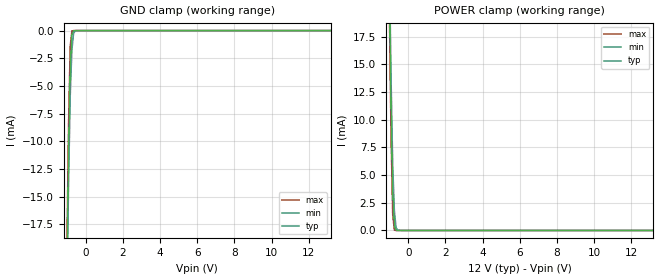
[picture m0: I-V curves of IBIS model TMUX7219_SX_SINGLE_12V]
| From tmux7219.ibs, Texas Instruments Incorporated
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[Model]   TMUX7219_SX_SINGLE_12V
Model_type   Terminator
|   typ   min   max
C_comp   44pF   44pF   44pF
[Voltage Range]   12   10.8   13.2
[Temperature Range]   27   125   -40
[Power Clamp Reference]   12   10.8   13.2
[GND Clamp Reference]   0   0   0
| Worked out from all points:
|   GND clamp passes 1 mA (typ) near -0.77 V on its own axis
|   POWER clamp passes 1 mA (typ) near -0.77 V on its own axis
[GND Clamp]
|   Voltage   I(typ)   I(min)   I(max)
-30V      -4.646A    -4.64A     -4.649A
-1.02V    -22.01mA   -24.41mA   -19.81mA
-930mV    -11.04mA   -13.89mA   -8.565mA
-840mV    -3.269mA   -5.934mA   -1.414mA
-750mV    -384.6uA   -1.761mA   -36.1uA
-660mV    -13.98uA   -270.8uA   -466.8nA
-570mV    -397.4nA   -19.97uA   -233.4nA
-210mV    0A         0A         0A
60V       0A         0A         0A
[POWER Clamp]
|   Voltage   I(typ)   I(min)   I(max)
-30V      4.646A     4.64A      4.649A
-1.02V    22.01mA    24.41mA    19.81mA
-930mV    11.04mA    13.89mA    8.565mA
-840mV    3.269mA    5.934mA    1.414mA
-750mV    384.6uA    1.761mA    36.1uA
-660mV    13.98uA    270.8uA    466.8nA
-570mV    397.4nA    19.97uA    233.4nA
-210mV    0A         0A         0A
60V       0A         0A         0A
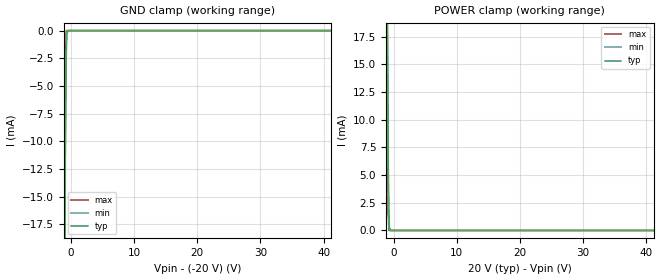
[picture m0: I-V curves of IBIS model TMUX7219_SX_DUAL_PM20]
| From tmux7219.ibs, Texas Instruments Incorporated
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[Model]   TMUX7219_SX_DUAL_PM20
Model_type   Terminator
|   typ   min   max
C_comp   33pF   33pF   33pF
[Voltage Range]   40   36   44
[Temperature Range]   27   125   -40
[Power Clamp Reference]   20   20   20
[GND Clamp Reference]   -20   -20   -20
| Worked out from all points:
|   GND clamp passes 1 mA (typ) near -0.77 V on its own axis
|   POWER clamp passes 1 mA (typ) near -0.77 V on its own axis
[GND Clamp]
|   Voltage   I(typ)   I(min)   I(max)
-30V      -4.646A    -4.714A    -4.649A
-1.02V    -22.01mA   -24.41mA   -19.81mA
-930mV    -11.04mA   -13.89mA   -8.565mA
-840mV    -3.269mA   -5.934mA   -1.414mA
-750mV    -384.6uA   -1.761mA   -36.11uA
-660mV    -13.98uA   -270.8uA   -471.2nA
-480mV    -8.39uA    -1.291uA   0A
-210mV    0A         0A         0A
60V       0A         0A         0A
[POWER Clamp]
|   Voltage   I(typ)   I(min)   I(max)
-30V      4.646A     4.714A     4.649A
-1.02V    22.01mA    24.41mA    19.81mA
-930mV    11.04mA    13.89mA    8.565mA
-840mV    3.269mA    5.934mA    1.414mA
-750mV    384.6uA    1.761mA    36.11uA
-660mV    13.98uA    270.8uA    471.2nA
-480mV    8.39uA     1.291uA    0A
-210mV    0A         0A         0A
60V       0A         0A         0A
